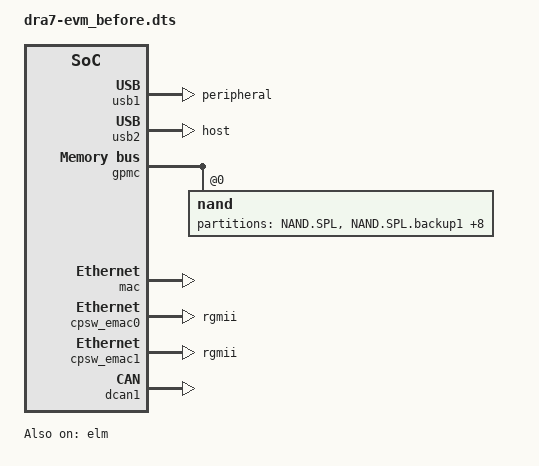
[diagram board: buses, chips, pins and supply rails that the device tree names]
		partition@5 {
			label = "QSPI.u-boot-spl-os";
			reg = <0x00140000 0x00010000>;
		};
		partition@6 {
			label = "QSPI.u-boot-env";
			reg = <0x00150000 0x00010000>;
		};
		partition@7 {
			label = "QSPI.u-boot-env.backup1";
			reg = <0x00160000 0x0010000>;
		};
		partition@8 {
			label = "QSPI.kernel";
			reg = <0x00170000 0x0800000>;
		};
		partition@9 {
			label = "QSPI.file-system";
			reg = <0x00970000 0x01690000>;
		};
	};
};

&usb1 {
	dr_mode = "peripheral";
	pinctrl-names = "default";
	pinctrl-0 = <&usb1_pins>;
};

&usb2 {
	dr_mode = "host";
	pinctrl-names = "default";
	pinctrl-0 = <&usb2_pins>;
};

&elm {
	status = "okay";
};

&gpmc {
	status = "okay";
	pinctrl-names = "default";
	pinctrl-0 = <&nand_flash_x16>;
	ranges = <0 0 0 0x01000000>;	/* minimum GPMC partition = 16MB */
	nand@0,0 {
		reg = <0 0 4>;		/* device IO registers */
		ti,nand-ecc-opt = "bch8";
		ti,elm-id = <&elm>;
		nand-bus-width = <16>;
		gpmc,device-width = <2>;
		gpmc,sync-clk-ps = <0>;
		gpmc,cs-on-ns = <0>;
		gpmc,cs-rd-off-ns = <80>;
		gpmc,cs-wr-off-ns = <80>;
		gpmc,adv-on-ns = <0>;
		gpmc,adv-rd-off-ns = <60>;
		gpmc,adv-wr-off-ns = <60>;
		gpmc,we-on-ns = <10>;
		gpmc,we-off-ns = <50>;
		gpmc,oe-on-ns = <4>;
		gpmc,oe-off-ns = <40>;
		gpmc,access-ns = <40>;
		gpmc,wr-access-ns = <80>;
		gpmc,rd-cycle-ns = <80>;
		gpmc,wr-cycle-ns = <80>;
		gpmc,bus-turnaround-ns = <0>;
		gpmc,cycle2cycle-delay-ns = <0>;
		gpmc,clk-activation-ns = <0>;
		gpmc,wait-monitoring-ns = <0>;
		gpmc,wr-data-mux-bus-ns = <0>;
		/* MTD partition table */
		/* All SPL-* partitions are sized to minimal length
		 * which can be independently programmable. For
		 * NAND flash this is equal to size of erase-block */
		#address-cells = <1>;
		#size-cells = <1>;
		partition@0 {
			label = "NAND.SPL";
			reg = <0x00000000 0x000020000>;
		};
		partition@1 {
			label = "NAND.SPL.backup1";
			reg = <0x00020000 0x00020000>;
		};
		partition@2 {
			label = "NAND.SPL.backup2";
			reg = <0x00040000 0x00020000>;
		};
		partition@3 {
			label = "NAND.SPL.backup3";
			reg = <0x00060000 0x00020000>;
		};
		partition@4 {
			label = "NAND.u-boot-spl-os";
			reg = <0x00080000 0x00040000>;
		};
		partition@5 {
			label = "NAND.u-boot";
			reg = <0x000c0000 0x00100000>;
		};
		partition@6 {
			label = "NAND.u-boot-env";
			reg = <0x001c0000 0x00020000>;
		};
		partition@7 {
			label = "NAND.u-boot-env.backup1";
			reg = <0x001e0000 0x00020000>;
		};
		partition@8 {
			label = "NAND.kernel";
			reg = <0x00200000 0x00800000>;
		};
		partition@9 {
			label = "NAND.file-system";
			reg = <0x00a00000 0x0f600000>;
		};
	};
};

&usb2_phy1 {
	phy-supply = <&ldousb_reg>;
};

&usb2_phy2 {
	phy-supply = <&ldousb_reg>;
};

&gpio7 {
	ti,no-reset-on-init;
	ti,no-idle-on-init;
};

&mac {
	status = "okay";
	pinctrl-names = "default", "sleep";
	pinctrl-0 = <&cpsw_default>;
	pinctrl-1 = <&cpsw_sleep>;
	dual_emac;
};

&cpsw_emac0 {
	phy_id = <&davinci_mdio>, <2>;
	phy-mode = "rgmii";
	dual_emac_res_vlan = <1>;
};

&cpsw_emac1 {
	phy_id = <&davinci_mdio>, <3>;
	phy-mode = "rgmii";
	dual_emac_res_vlan = <2>;
};

&davinci_mdio {
	pinctrl-names = "default", "sleep";
	pinctrl-0 = <&davinci_mdio_default>;
	pinctrl-1 = <&davinci_mdio_sleep>;
};

&dcan1 {
	status = "ok";
	pinctrl-names = "default", "sleep";
	pinctrl-0 = <&dcan1_pins_default>;
	pinctrl-1 = <&dcan1_pins_sleep>;
};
